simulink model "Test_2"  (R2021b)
settings: Solver=FixedStepAuto  StartTime=0.0  StopTime=60
undefined symbols (not defined in the file): Ion, Lithium, Pe
libraries: fl_lib x31, nesl_utility x24, sdl_lib x11, simulink x7, simulink_extras x3, spsBatteryLib x1, spsCurrentVoltageSimscapeInterfaceLib x1, slpidlib x1, SignalEditorBlockLib x1, spspowerguiLib x1
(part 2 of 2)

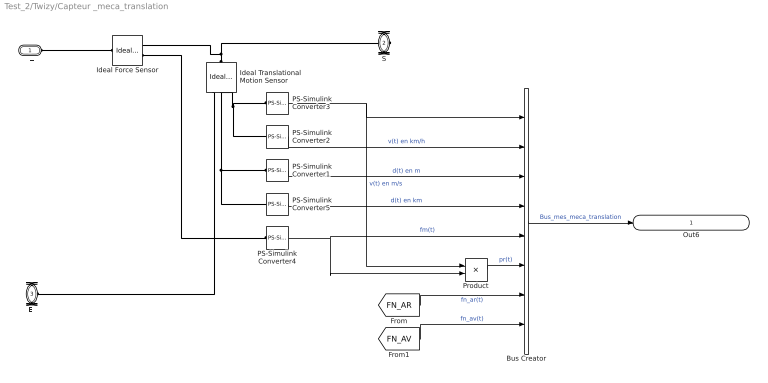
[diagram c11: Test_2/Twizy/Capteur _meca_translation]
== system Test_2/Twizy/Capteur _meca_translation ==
  Bus Creator : BusCreator  Inputs=8
  Ideal Force Sensor : fl_lib/Mechanical/Mechanical Sensors/Ideal Force Sensor
  Ideal Translational Motion Sensor : fl_lib/Mechanical/Mechanical Sensors/Ideal Translational Motion Sensor  offset=0 m
  PS-Simulink Converter1 : nesl_utility/PS-Simulink Converter  PhysicalDomain=network_engine_domain  SubClassName=ps_output  LeftPortType=input  RightPortType=output  PseudoPeriodic=off  Frequencies=[]  Unit=m  AffineConversion=off
  PS-Simulink Converter2 : nesl_utility/PS-Simulink Converter  PhysicalDomain=network_engine_domain  SubClassName=ps_output  LeftPortType=input  RightPortType=output  PseudoPeriodic=off  Frequencies=[]  Unit=km/hr  AffineConversion=off
  PS-Simulink Converter3 : nesl_utility/PS-Simulink Converter  PhysicalDomain=network_engine_domain  SubClassName=ps_output  LeftPortType=input  RightPortType=output  PseudoPeriodic=off  Frequencies=[]  Unit=m/s  AffineConversion=off
  PS-Simulink Converter4 : nesl_utility/PS-Simulink Converter  PhysicalDomain=network_engine_domain  SubClassName=ps_output  LeftPortType=input  RightPortType=output  PseudoPeriodic=off  Frequencies=[]  Unit=N  AffineConversion=off
  PS-Simulink Converter5 : nesl_utility/PS-Simulink Converter  PhysicalDomain=network_engine_domain  SubClassName=ps_output  LeftPortType=input  RightPortType=output  PseudoPeriodic=off  Frequencies=[]  Unit=km  AffineConversion=off
  Product : Product
  E+ : PMIOPort  Side=Left
  S : PMIOPort  Port=2  Side=Right
  E- : PMIOPort  Port=3  Side=Left
  Out6 : Outport  VectorParamsAs1DForOutWhenUnconnected=off
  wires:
  PS-Simulink Converter3/1 -> Product/1, Bus Creator/1  "v(t) en m/s"
  PS-Simulink Converter4/1 -> Bus Creator/5, Product/2  "fm(t)"
  Product/1 -> Bus Creator/6  "pr(t)"
  Bus Creator/1 -> Out6/1  "Bus_mes_meca_translation"
  PS-Simulink Converter1/1 -> Bus Creator/3  "d(t) en m"
  [FN_AR] -> Bus Creator/7  "fn_ar(t)"
  [FN_AV] -> Bus Creator/8  "fn_av(t)"
  PS-Simulink Converter2/1 -> Bus Creator/2  "v(t) en km/h"
  PS-Simulink Converter5/1 -> Bus Creator/4  "d(t) en km"
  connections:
  PS-Simulink Converter4/LConn1 -- Ideal Force Sensor/RConn2
  Ideal Translational Motion Sensor/LConn1 -- Ideal Force Sensor/RConn1 -- S/RConn1
  PS-Simulink Converter3/LConn1 -- PS-Simulink Converter2/LConn1 -- Ideal Translational Motion Sensor/RConn2
  Ideal Force Sensor/LConn1 -- E+/RConn1
  Ideal Translational Motion Sensor/RConn1 -- E-/RConn1
  PS-Simulink Converter1/LConn1 -- Ideal Translational Motion Sensor/RConn3 -- PS-Simulink Converter5/LConn1

== matlab function Test_2/Modele ensemble variateur Sevcon et moteur asynchrone Letrika
en fonctionnement moyen/Capteur meca rotation/MATLAB Function2 ==
function Quadrant_meca = fcn(Cm,Nm)
if Nm > 1
    if Cm > 0
        Quadrant_meca = 1;
    elseif Cm < 0
        Quadrant_meca = 4;
    else
        Quadrant_meca = 0;
    end
elseif Nm < -1
    if Cm > 0
        Quadrant_meca = 2;
    elseif Cm < 0
        Quadrant_meca = 3;
    else
        Quadrant_meca = 0;
    end
else
    Quadrant_meca = 0;
end
end

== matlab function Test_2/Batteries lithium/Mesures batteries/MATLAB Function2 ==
function Quadrant_elec = fcn(I_bat,U_bat)
if U_bat > 0.8
    if I_bat > 0.3
        Quadrant_elec = 1;
    elseif I_bat < -0.5
        Quadrant_elec = 4;
    else
        Quadrant_elec = 0;
    end
elseif U_bat < -0.8
    if I_bat > 0.5
        Quadrant_elec = 2;
    elseif I_bat < -0.5
        Quadrant_elec = 3;
    else
        Quadrant_elec = 0;
    end
else
    Quadrant_elec = 0;
end
end

== matlab function Test_2/Modele ensemble variateur Sevcon et moteur asynchrone Letrika
en fonctionnement moyen/MATLAB Function ==
function [T_out,P_meca]= fcn(Consigne_frequence, T_in,Nn,Tn,Un,U_bat,Nmes)
if U_bat <= Un
    k_corr = (U_bat/Un).^2;
else
    k_corr = 1;
end
P_max = Tn*(2*pi*Nn/60)*k_corr;

if Consigne_frequence~=0
    if abs(Nmes)<=Nn
        if abs(T_in)>=Tn*k_corr
            T_out=Tn*sign(T_in)*k_corr;
        else
            T_out=T_in*k_corr;
        end
    else
        if abs(T_in)>=P_max/(2*pi*Nmes/60)
            T_out=sign(T_in)*P_max/(2*pi*Nmes/60);
        else
            T_out=T_in;
        end
    end
else
    T_out=0;
end

P_meca = T_out*2*pi*Nmes/60;

end

== matlab function Test_2/Modele ensemble variateur Sevcon et moteur asynchrone Letrika
en fonctionnement moyen/MATLAB Function1 ==
function I_bat = fcn(Pmeca,rend_var,rend_mot,U_bat)
if Pmeca < 0
    P_elec = Pmeca*(rend_mot/100)*(rend_var/100);    
elseif Pmeca > 0
    P_elec = Pmeca/((rend_mot/100)*(rend_var/100)); 
else
    P_elec = 0;   
end
I_bat = P_elec/U_bat;
end
